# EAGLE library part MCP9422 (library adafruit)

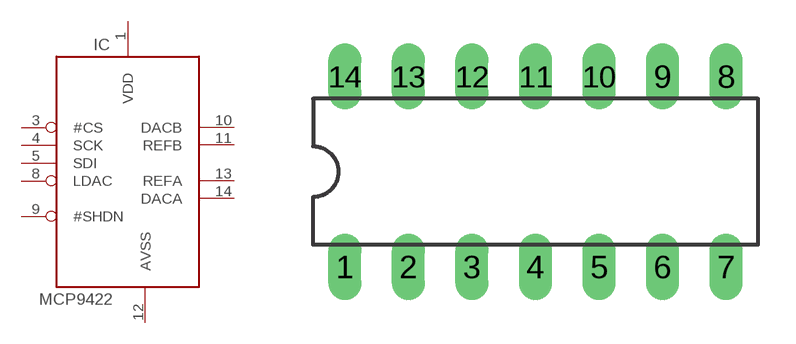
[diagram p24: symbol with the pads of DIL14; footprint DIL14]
Designator prefix IC

## MCP9422  [DIL14]
1  VDD  sup
3  #CS  in
4  SCK  in
5  SDI  in
8  LDAC  in
9  #SHDN  in
10  DACB  out
11  REFB  in
12  AVSS  sup
13  REFA  in
14  DACA  out

## Footprint DIL14 (pad centres in mm)
Dual In Line Package
drill 0.813 long: 1 -7.62,-3.81; 2 -5.08,-3.81; 3 -2.54,-3.81; 4 0,-3.81; 5 2.54,-3.81; 6 5.08,-3.81; 7 7.62,-3.81; 8 7.62,3.81; 9 5.08,3.81; 10 2.54,3.81; 11 0,3.81; 12 -2.54,3.81; 13 -5.08,3.81; 14 -7.62,3.81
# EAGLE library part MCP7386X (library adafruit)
MCP7386x 4.1, 4.2, 8.2, 8.4 LiPoly battery charger chip family, with wide DC input, thermal cutoff, adjustable curret, and indicator LEDs

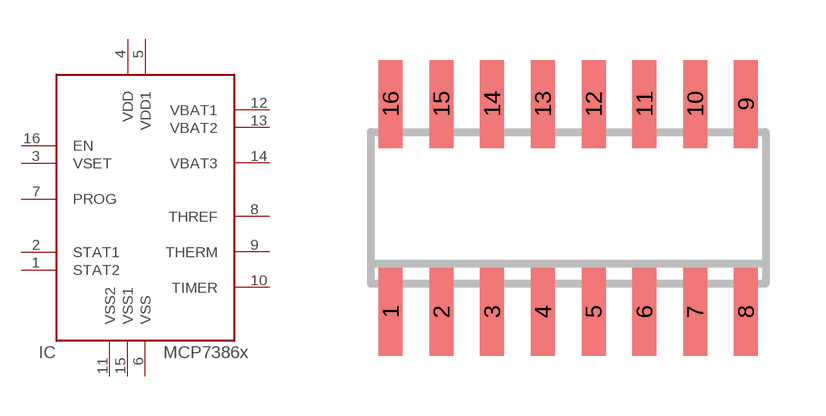
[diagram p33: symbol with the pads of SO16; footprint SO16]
Designator prefix IC

## MCP7386XS  [SO16]
1  STAT2  out
2  STAT1  out
3  VSET  in
4  VDD  pwr
5  VDD1  pwr
6  VSS  pwr
7  PROG  pas
8  THREF  pas
9  THERM  pas
10  TIMER  pas
11  VSS2  pwr
12  VBAT1  in
13  VBAT2  in
14  VBAT3  in
15  VSS1  pwr
16  EN  in

## Footprint SO16 (pad centres in mm)
SMALL OUTLINE INTEGRATED CIRCUIT body 3.9 mm/JEDEC MS-012AC
smd 0.6 x 2.2: 1 -4.445,-2.6; 2 -3.175,-2.6; 3 -1.905,-2.6; 4 -0.635,-2.6; 5 0.635,-2.6; 6 1.905,-2.6; 7 3.175,-2.6; 8 4.445,-2.6; 9 4.445,2.6; 10 3.175,2.6; 11 1.905,2.6; 12 0.635,2.6; 13 -0.635,2.6; 14 -1.905,2.6; 15 -3.175,2.6; 16 -4.445,2.6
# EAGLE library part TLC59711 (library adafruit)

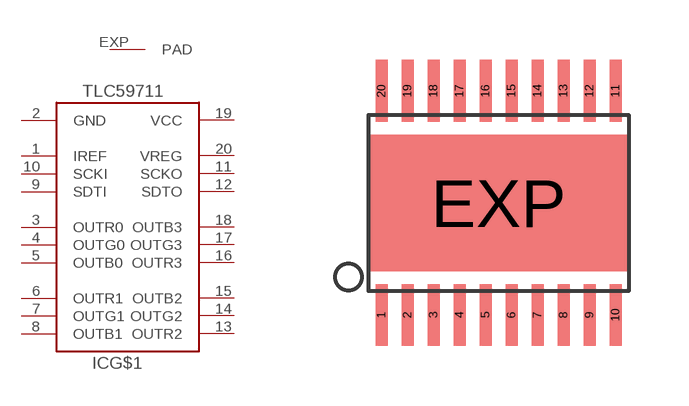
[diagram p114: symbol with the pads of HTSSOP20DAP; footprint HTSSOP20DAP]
Designator prefix IC; gates G$1=TLC59711 G$2=THERMAL_PAD

## TLC59711  [HTSSOP20DAP]
1  G$1:IREF
2  G$1:GND  pwr
3  G$1:OUTR0  oc
4  G$1:OUTG0  oc
5  G$1:OUTB0  oc
6  G$1:OUTR1  oc
7  G$1:OUTG1  oc
8  G$1:OUTB1  oc
9  G$1:SDTI  in
10  G$1:SCKI  in
11  G$1:SCKO  out
12  G$1:SDTO  out
13  G$1:OUTR2  oc
14  G$1:OUTG2  oc
15  G$1:OUTB2  oc
16  G$1:OUTR3  oc
17  G$1:OUTG3  oc
18  G$1:OUTB3  oc
19  G$1:VCC  pwr
20  G$1:VREG
EXP  G$2:PAD  pas

## Footprint HTSSOP20DAP (pad centres in mm)
smd 0.3 x 1.55: 1 -2.925,-2.8; 2 -2.275,-2.8; 3 -1.625,-2.8; 4 -0.975,-2.8; 5 -0.325,-2.8; 6 0.325,-2.8; 7 0.975,-2.8; 8 1.625,-2.8; 9 2.275,-2.8; 10 2.925,-2.8; 11 2.925,2.8; 12 2.275,2.8; 13 1.625,2.8; 14 0.975,2.8; 15 0.325,2.8; 16 -0.325,2.8; 17 -0.975,2.8; 18 -1.625,2.8; 19 -2.275,2.8; 20 -2.925,2.8
smd 6.5 x 3.4: EXP 0,0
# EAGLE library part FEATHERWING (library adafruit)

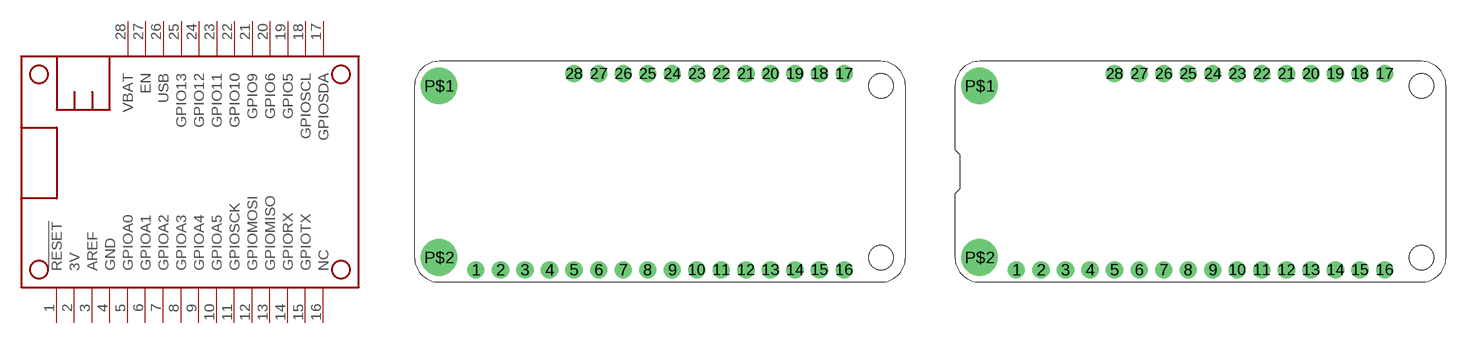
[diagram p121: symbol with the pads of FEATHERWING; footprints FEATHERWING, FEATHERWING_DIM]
Designator prefix MS

## FEATHERWING  [FEATHERWING]
1  !RESET  in
2  3V  sup
3  AREF  pas
4  GND  pwr
5  GPIOA0
6  GPIOA1
7  GPIOA2
8  GPIOA3
9  GPIOA4
10  GPIOA5
11  GPIOSCK
12  GPIOMOSI
13  GPIOMISO
14  GPIORX
15  GPIOTX
16  NC  pas
17  GPIOSDA
18  GPIOSCL
19  GPIO5
20  GPIO6
21  GPIO9
22  GPIO10
23  GPIO11
24  GPIO12
25  GPIO13
26  USB  sup
27  EN  pas
28  VBAT  sup

## FEATHERWING_NODIM  [FEATHERWING_DIM]
Pads as for FEATHERWING

## Footprint FEATHERWING (pad centres in mm)
drill 1 pad 1.778: 1 6.35,1.27; 2 8.89,1.27; 3 11.43,1.27; 4 13.97,1.27; 5 16.51,1.27; 6 19.05,1.27; 7 21.59,1.27; 8 24.13,1.27; 9 26.67,1.27; 10 29.21,1.27; 11 31.75,1.27; 12 34.29,1.27; 13 36.83,1.27; 14 39.37,1.27; 15 41.91,1.27; 16 44.45,1.27; 17 44.45,21.59; 18 41.91,21.59; 19 39.37,21.59; 20 36.83,21.59; 21 34.29,21.59; 22 31.75,21.59; 23 29.21,21.59; 24 26.67,21.59; 25 24.13,21.59; 26 21.59,21.59; 27 19.05,21.59; 28 16.51,21.59
drill 2.5 pad 3.81: P$1 2.54,20.32; P$2 2.54,2.54
hole 2.54 at 48.26,20.32
hole 2.54 at 48.26,2.54

## Footprint FEATHERWING_DIM (pad centres in mm)
drill 1 pad 1.778: 1 6.35,1.27; 2 8.89,1.27; 3 11.43,1.27; 4 13.97,1.27; 5 16.51,1.27; 6 19.05,1.27; 7 21.59,1.27; 8 24.13,1.27; 9 26.67,1.27; 10 29.21,1.27; 11 31.75,1.27; 12 34.29,1.27; 13 36.83,1.27; 14 39.37,1.27; 15 41.91,1.27; 16 44.45,1.27; 17 44.45,21.59; 18 41.91,21.59; 19 39.37,21.59; 20 36.83,21.59; 21 34.29,21.59; 22 31.75,21.59; 23 29.21,21.59; 24 26.67,21.59; 25 24.13,21.59; 26 21.59,21.59; 27 19.05,21.59; 28 16.51,21.59
drill 2.5 pad 3.81: P$1 2.54,20.32; P$2 2.54,2.54
hole 2.54 at 48.26,20.32
hole 2.54 at 48.26,2.54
